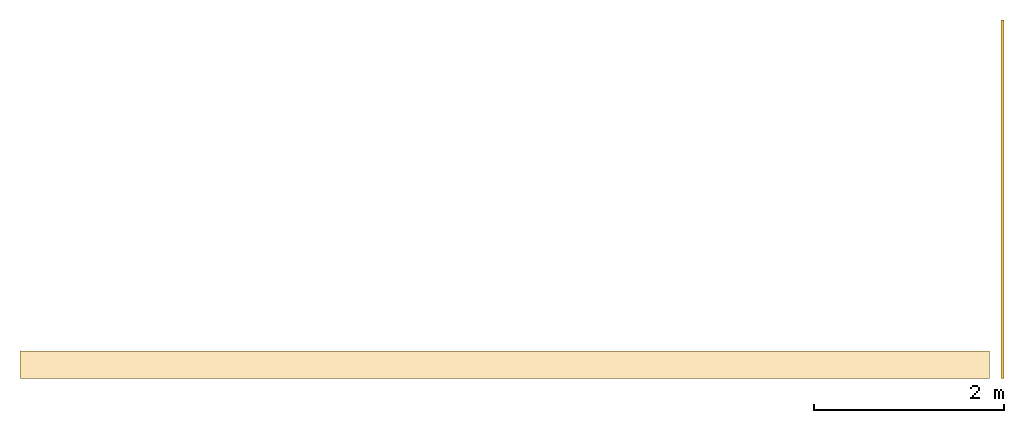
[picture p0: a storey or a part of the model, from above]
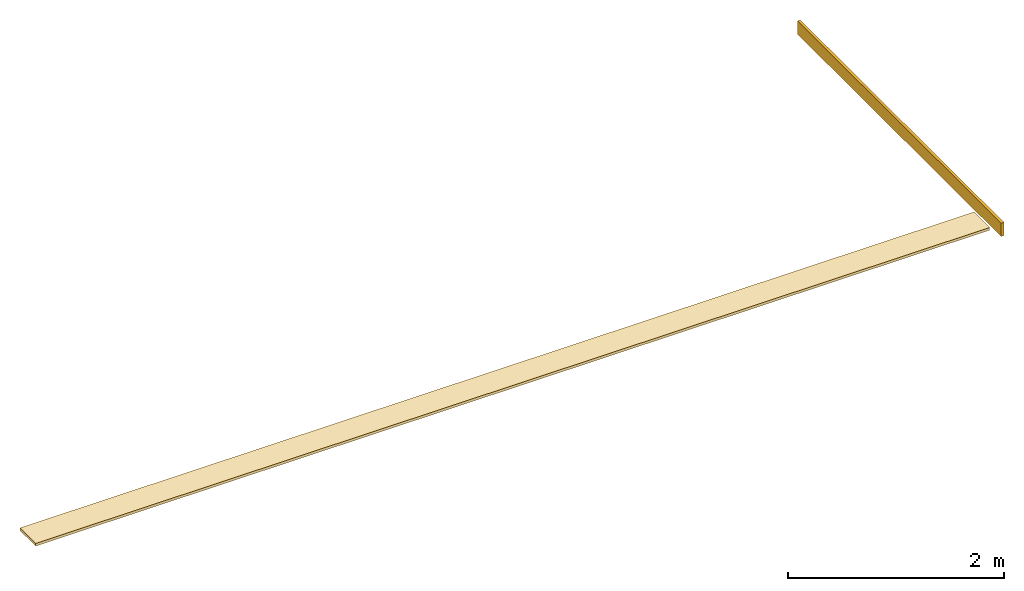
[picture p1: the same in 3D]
Properties of the parts of a building model (IFC2X3)

# File
Description: ViewDefinition [CoordinationView]
File name: GM.TO-350-208.1 (EDITED).ifc (Edited by Naviate Simple BIM 2022 version 6)
Time: 2026-03-12T20:13:48+01:00
Written by: ODA SDAI 24.12
Made in: Autodesk Revit 25.4.20.11 (ENU) - IFC 25.4.0.27

# IfcProject, A181143
LongName: UNSØ; Phase: Forprosjekt

# IfcSite (4)
Name | RefLatitude | RefLongitude | RefElevation (mm)
ENGM | 42, 24, 53, 508911 | -71, -15, -29, -58837 | -4.85124e-10
Gardermoen |  |  | 0
Default | 42, 23, 13, 199999 | -71, -14, -31, -199999 | 0 | Title Text - Mottaker 01 Firma_CW: Avinor; Mottaker 06 Kontaktperson _CW: Martin Liudalen; Mottaker 08 Kontaktperson _CW: Jesper Mæx Moe; Mottaker 02 Funksjon_CW: BL; Modellstatus_CW: Beskriv kort om status til modellen og hvilke område som er kontrollert.; Mottaker 07 Funksjon_CW: RIKT; Mottaker 05 Firma _CW: COWI/AAS-JAKOBSEN; Mottaker 06 Firma _CW: COWI/ASPLAN VIAK; Mottaker 07 Firma _CW: COWI/ASPLAN VIAK; Mottaker 05 Funksjon_CW: RIB; Mottaker 06 Funksjon_CW: RIE; Mottaker 08 Funksjon_CW: RIV; Mottaker 04 Funksjon_CW: ARK; Mottaker 02 Firma _CW: SWECO; Mottaker 10 Funksjon_CW: RIBR; Mottaker 07 Kontaktperson _CW: Kent Fagerli; Mottaker 02 Kontaktperson _CW: Øyvind Taule; Mottaker 03 Kontaktperson _CW: Kjetil Hoftvedt; Mottaker 03 Funksjon_CW: PGL; Mottaker 01 Funksjon_CW: BH; Mottaker 05 Kontaktperson _CW: Magne Fredheim; Mottaker 04 Kontaktperson _CW: Ivar Ivarsøy; Mottaker 03 Firma _CW: COWI; Mottaker 08 Firma _CW: COWI; Mottaker 01 Kontaktperson _CW: Kontakperson; Mottaker 04 Firma _CW: NORDIC; Other - Client Name: Avinor; Project Name: Utvidelse non-schengen; Category: Project Information; Project Status: Utførelse; Project Address: Gardermoen; Project Number: A173040; Project Issue Date: 24.12.2013; Identity Data - Oppdragsansvarlig_CW: Kjetil Hoftvedt; Workset: Project Info; Edited by: tagr
ENGM | 59, 54, 44, 239196 | 10, 45, 0, 0 | 0 | MagiCAD Pset_Site - Reference longitude: 10, 45, 0, 0; Reference elevation: 0; Reference latitude: 59, 54, 44, 239196; Name: ENGM

# IfcBuilding (4)
Name
TH | LongName: TH; Pset_BuildingCommon - NumberOfStoreys: 8
THO
 | Pset_BuildingCommon - NumberOfStoreys: 5; Identity Data - Oppdragsansvarlig_CW: Kjetil Hoftvedt; Workset: Project Info; Edited by: tagr; Other - Client Name: Avinor; Project Name: Utvidelse non-schengen; Category: Project Information; Project Status: Utførelse; Project Address: Gardermoen; Project Number: A173040; Project Issue Date: 24.12.2013; Title Text - Mottaker 01 Firma_CW: Avinor; Mottaker 06 Kontaktperson _CW: Martin Liudalen; Mottaker 08 Kontaktperson _CW: Jesper Mæx Moe; Mottaker 02 Funksjon_CW: BL; Modellstatus_CW: Beskriv kort om status til modellen og hvilke område som er kontrollert.; Mottaker 07 Funksjon_CW: RIKT; Mottaker 05 Firma _CW: COWI/AAS-JAKOBSEN; Mottaker 06 Firma _CW: COWI/ASPLAN VIAK; Mottaker 07 Firma _CW: COWI/ASPLAN VIAK; Mottaker 08 Funksjon_CW: RIV; Mottaker 06 Funksjon_CW: RIE; Mottaker 05 Funksjon_CW: RIB; Mottaker 04 Funksjon_CW: ARK; Mottaker 02 Firma _CW: SWECO; Mottaker 10 Funksjon_CW: RIBR; Mottaker 07 Kontaktperson _CW: Kent Fagerli; Mottaker 02 Kontaktperson _CW: Øyvind Taule; Mottaker 03 Kontaktperson _CW: Kjetil Hoftvedt; Mottaker 03 Funksjon_CW: PGL; Mottaker 01 Funksjon_CW: BH; Mottaker 05 Kontaktperson _CW: Magne Fredheim; Mottaker 04 Kontaktperson _CW: Ivar Ivarsøy; Mottaker 03 Firma _CW: COWI; Mottaker 08 Firma _CW: COWI; Mottaker 01 Kontaktperson _CW: Kontakperson; Mottaker 04 Firma _CW: NORDIC
TH | MagiCAD Pset_Building - Building name: TH

# IfcBuildingStorey (3)
Name | In | Elevation (mm)
Nivå G | THO | 0
Nivå F | THO | 0
Nivå F - 0,7 m | TH | 210200 | MagiCAD Pset_Storey - Name: Nivå F - 0,7 m

# IfcBuildingStorey: Level:CW_Level Elektro, Nivå F - 0,7 m
LongName: Nivå F - 0,7 m; Elevation: 210200 mm
Constraints(Type) - Elevation Base: Survey Point
Pset_ProductRequirements - Name: Nivå F - 0,7 m; sets with these values: 2
Identity Data - Name: Nivå F - 0,7 m; Building Story: yes; Structural: no; Workset: Shared Levels and Grids
Dimensions - Computation Height: 0 mm
Other - Type Id: 305; Family and Type: Level: CW_Level Elektro; Category: Levels; Family: Level; Type: CW_Level Elektro
Constraints - Elevation: 210200 mm
Identity Data(Type) - Workset: Level Types; Type Name: CW_Level Elektro
Graphics(Type) - Symbol: CW Nivåhode : COWI Nivåhode; Line Pattern: Grid Line; Color: 0; Symbol at End 1 Default: yes; Symbol at End 2 Default: yes; Line Weight: 1
Other(Type) - Category: Levels; Family Name: Level

# IfcBuildingStorey: Level:T2 - Kote, Nivå F - 0,7 m
In: TH
LongName: Nivå F - 0,7 m; Elevation: 210200 mm
Pset_ProductRequirements - Name: Nivå F - 0,7 m; sets with these values: 2

# IfcBuildingElementProxy: System Panel:A255 - HI-L01 - SP (10)
In: Nivå F - 0,7 m
Type - Material: lamellhimling(Panel)
Pset_BuildingElementProxyCommon - Reference: A255 - HI-L01 - SP; sets with these values: 2
AVINOR - 08_Status: S4; 05_ID-nummer: +TH=255.002-ID0011; 07_Fase: F90; 02_Prosjekt: A173040; 06_Omrade: TH; 04_Kontrakt: 185259; 03_Ansvar: 185239; 01_Lufthavnkode: ENGM
ePset_LocationTool - Splitting: ORIGINAL
ePset_Simplebim - Assembly Level: Leaf
ePset_SimplebimBasicQuantities - Height (Simplebim): 75 mm
Name (System Panel:A255 - HI-L01 - SP:...) | Area, largest surface, net (Simplebim) (m2) | Volume, net (Simplebim) (m3) | Thickness (Simplebim) (mm) | Length (Simplebim) (mm)
51589264 | 2.73781 | 0.205336 | 805 | 3600
51589265 | 3.07997 | 0.230997 | 900 | 3600
51589266 | 3.07981 | 0.230986 | 900 | 3600
51589267 | 3.07997 | 0.230997 | 900 | 3600
51589947 | 2.74905 | 0.206179 | 804.8 | 3600
51589461 | 0.435362 | 0.0326522 | 542.5 | 805
51589462 | 0.403017 | 0.0302263 | 452 | 900
51589463 | 0.40325 | 0.0302438 | 452 | 900
51589464 | 0.40325 | 0.0302438 | 452 | 900
51589948 | 0.35963 | 0.0269722 | 452 | 804.8

# IfcColumn: D20 (16)
In: Nivå F
Description: D20; Material: STEEL/S355
Pset_ColumnCommon - Reference: D20
ePset_LocationTool - Splitting: ORIGINAL
ePset_SimplebimBasicQuantities - Weight, as steel (Simplebim): 0.555079 kg; Volume, net (Simplebim): 0.0000707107 m3; Area, sides, net (Simplebim): 0.0153073 m2; Width (Simplebim): 20 mm; Depth (Simplebim): 20 mm; Height (Simplebim): 250 mm
ePset_Simplebim - Assembly Level: Leaf
Tekla Quantity - AREA_NET: 0.01587 m2; AREA_GROSS: 0.01587 m2; WEIGTH_GROSS: 0.55508 kg; WEIGTH_NET: 0.55508 kg; Width: 20 mm; Heigth: 20 mm; Length: 250 mm; VOLUME_GROSS: 0.00006 m3; VOLUME_NET: 0.00006 m3
AVINOR - 05_ID-nummer: +TH=222.027; 08_Status: S4; 07_Fase: F90; 04_Kontrakt: 185257; 02_Prosjekt: A173040; 06_Omrade: TH; 03_Ansvar: 185233; 01_Lufthavnkode: ENGM

# IfcColumn: D600 (4)
In: Nivå F
Description: D600
ePset_SimplebimBasicQuantities - Depth (Simplebim): 600 mm
ePset_LocationTool - Splitting: ORIGINAL
Tekla Quantity - Width: 600 mm; Heigth: 600 mm
Pset_ColumnCommon - Reference: D600
ePset_Simplebim - Assembly Level: Leaf
AVINOR - 05_ID-nummer: +TH=222.027; 08_Status: S4; 07_Fase: F90; 04_Kontrakt: 185257; 02_Prosjekt: A173040; 06_Omrade: TH; 03_Ansvar: 185233; 01_Lufthavnkode: ENGM
Name | Material | Volume, net (Simplebim) (m3) | Width (Simplebim) (mm) | Height (Simplebim) (mm) | Area, sides, net (Simplebim) (m2) | Weight, as steel (Simplebim) (kg) | VOLUME_GROSS (m3) = VOLUME_NET (m3) | AREA_NET (m2) = AREA_GROSS (m2) | Length (mm) | WEIGTH_GROSS (kg) = WEIGTH_NET (kg)
2 x INNSTØPNGODS | STEEL/S355 | 0.00844746 | 30 | 600 | 0.0564906 | 66.3126 | 0.00845 | 0.61965 | 30 | 66.3126
2 x PREFABSØYLE | CONCRETE/C45/55 | 1.03481 | 600 | 3675 | 6.92009 | 8123.29 | 1.03481 | 7.48326 | 3675 | 2483.55

# IfcColumn: HEA180 (2)
In: Nivå F
Description: HEA180; Material: STEEL/S355
ePset_LocationTool - Splitting: ORIGINAL
Tekla Quantity - AREA_GROSS: 3.72224 m2; WEIGTH_GROSS: 129.12 kg; VOLUME_GROSS: 0.01645 m3; Heigth: 171 mm; Width: 180 mm; Length: 3635 mm
AVINOR - 08_Status: S4; 07_Fase: F90; 05_ID-nummer: +TH=222.037; 02_Prosjekt: A173040; 06_Omrade: TH; 04_Kontrakt: 185259; 03_Ansvar: 185233; 01_Lufthavnkode: ENGM; 09_Arbeidspakke: AP02
ePset_SimplebimBasicQuantities - Width (Simplebim): 171 mm; Depth (Simplebim): 180 mm; Height (Simplebim): 3635 mm
ePset_Simplebim - Assembly Level: Leaf
Pset_ColumnCommon - Reference: HEA180
Name | WEIGTH_NET (kg) = Weight, as steel (Simplebim) (kg) | VOLUME_NET (m3) | AREA_NET (m2) | Area, sides, net (Simplebim) (m2) | Volume, net (Simplebim) (m3)
STÅLSØYLE | 120.993 | 0.01541 | 3.75515 | 3.74648 | 0.0154131
STÅLSØYLE | 118.369 | 0.01508 | 3.68478 | 3.67612 | 0.0150788

# IfcColumn: RHS80*5, STÅLSØYLE
In: Nivå F
Description: RHS80*5; Material: STEEL/S355
Pset_ColumnCommon - Reference: RHS80*5
AVINOR - 08_Status: S4; 07_Fase: F90; 05_ID-nummer: +TH=222.036; 02_Prosjekt: A173040; 06_Omrade: TH; 04_Kontrakt: 185259; 03_Ansvar: 185233; 09_Arbeidspakke: AP01; 01_Lufthavnkode: ENGM
ePset_LocationTool - Splitting: ORIGINAL
ePset_SimplebimBasicQuantities - Weight, as steel (Simplebim): 42.7433 kg; Area, sides, net (Simplebim): 2.178 m2; Volume, net (Simplebim): 0.005445 m3; Width (Simplebim): 80 mm; Depth (Simplebim): 80 mm; Height (Simplebim): 3630 mm
ePset_Simplebim - Assembly Level: Leaf
Tekla Quantity - WEIGTH_NET: 42.7433 kg; AREA_NET: 1.1632 m2; WEIGTH_GROSS: 42.4583 kg; AREA_GROSS: 1.12167 m2; VOLUME_NET: 0.00545 m3; VOLUME_GROSS: 0.00542 m3; Width: 80 mm; Heigth: 80 mm; Length: 3630 mm

# IfcColumn: UPE180, STÅLSØYLE
In: Nivå F
Description: UPE180; Material: STEEL/S355
Pset_ColumnCommon - Reference: UPE180
Tekla Quantity - VOLUME_NET: 0.00945 m3; AREA_GROSS: 2.31318 m2; WEIGTH_NET: 74.1989 kg; VOLUME_GROSS: 0.00909 m3; AREA_NET: 2.29086 m2; Width: 75 mm; Heigth: 180 mm; Length: 3620 mm; WEIGTH_GROSS: 71.3267 kg
AVINOR - 08_Status: S4; 07_Fase: F90; 05_ID-nummer: +TH=222.038; 02_Prosjekt: A173040; 06_Omrade: TH; 04_Kontrakt: 185259; 03_Ansvar: 185233; 01_Lufthavnkode: ENGM; 09_Arbeidspakke: AP02
ePset_SimplebimBasicQuantities - Weight, as steel (Simplebim): 74.1989 kg; Volume, net (Simplebim): 0.0094521 m3; Area, sides, net (Simplebim): 2.28548 m2; Width (Simplebim): 75 mm; Depth (Simplebim): 180 mm; Height (Simplebim): 3620 mm
ePset_Simplebim - Assembly Level: Leaf
ePset_LocationTool - Splitting: ORIGINAL

# IfcCovering (6)
AVINOR - 08_Status: S4; 07_Fase: F90; 04_Kontrakt: 185257; 02_Prosjekt: A173040; 06_Omrade: TH; 03_Ansvar: 185233; 01_Lufthavnkode: ENGM
Tekla Surface Treatment - Content Type: SURFACING; Aaj_forskaltyp: 0; Aaj_forskalobjtyp: 0; IFC_BUILDING: TH; Type: Steel finish
ePset_Simplebim - Assembly Level: Leaf
Name | In | Volume, net (Simplebim) (m3) | Width (Simplebim) (mm) | Height (Simplebim) (mm) | Area, largest surface, net (Simplebim) (m2) | Length (Simplebim) (mm) | 05_ID-nummer | IFC_BUILDING_STOREY | Name | Splitting
2 x SurfaceTreatment | Nivå F | 0.0164925 | 30 | 150 | 0.54975 | 3665 | +TH=222.035 | Nivå F | BRANNBESKSØYLE | ORIGINAL | Material: Undefined/MINERALULL; Tekla Surface Treatment - Weight: 0.32985 kg; Area: 0.54975 m2
2 x SurfaceTreatment | Nivå G | 0.0886525 | 290 | 30 | 2.95508 | 10190 | +TH=223.202 | Nivå G | BRANNBESKBJELKE | RESULT
2 x SurfaceTreatment | Nivå G | 0.0169557 | 30 | 150 | 0.56519 | 3768 | +TH=223.202 | Nivå G | BRANNBESKBJELKE | RESULT

# IfcCovering: A255 - HI-L01 - Panel:A255 - HI-L01 - Panel (38)
In: Nivå F - 0,7 m
Type - PredefinedType: CEILING; Material: lamellhimling(Panel)
ePset_SimplebimBasicQuantities - Height (Simplebim): 75 mm
ePset_LocationTool - Splitting: ORIGINAL
Pset_CoveringCommon - Reference: A255 - HI-L01 - Panel; sets with these values: 2
AVINOR - 08_Status: S4; 05_ID-nummer: +TH=255.002-ID0011; 07_Fase: F90; 02_Prosjekt: A173040; 06_Omrade: TH; 04_Kontrakt: 185259; 03_Ansvar: 185239; 01_Lufthavnkode: ENGM
ePset_Simplebim - Assembly Level: Leaf
Name (A255 - HI-L01 - Panel:A255 - HI-L01 - Panel:...) | Volume, net (Simplebim) (m3) | Area, largest surface, net (Simplebim) (m2) | Length (Simplebim) (mm) | Width (Simplebim) (mm)
51590143 | 0.108071 | 1.44095 | 1790 | 805
51589183 | 0.120825 | 1.611 | 1790 | 900
51589185 | 0.120825 | 1.611 | 1790 | 900
51589187 | 0.120825 | 1.611 | 1790 | 900
51589189 | 0.120825 | 1.611 | 1790 | 900
51589191 | 0.120825 | 1.611 | 1790 | 900
51589193 | 0.120825 | 1.611 | 1790 | 900
51589195 | 0.120825 | 1.611 | 1790 | 900
51589197 | 0.120825 | 1.611 | 1790 | 900
51589199 | 0.120825 | 1.611 | 1790 | 900
51589201 | 0.120825 | 1.611 | 1790 | 900
51589203 | 0.120825 | 1.611 | 1790 | 900
51589205 | 0.120825 | 1.611 | 1790 | 900
51589207 | 0.120825 | 1.611 | 1790 | 900
51589209 | 0.120825 | 1.611 | 1790 | 900
51589211 | 0.0986469 | 1.31529 | 1790 | 734.8
51590144 | 0.243 | 3.24 | 3600 | 900
51589216 | 0.243 | 3.24 | 3600 | 900
51589217 | 0.243 | 3.24 | 3600 | 900
51589218 | 0.243 | 3.24 | 3600 | 900
51589219 | 0.243 | 3.24 | 3600 | 900
51589220 | 0.243 | 3.24 | 3600 | 900
51589221 | 0.243 | 3.24 | 3600 | 900
51589222 | 0.243 | 3.24 | 3600 | 900
51590145 | 0.243 | 3.24 | 3600 | 900
51589226 | 0.243 | 3.24 | 3600 | 900
51589227 | 0.243 | 3.24 | 3600 | 900
51589232 | 0.03051 | 0.4068 | 900 | 452
51589233 | 0.03051 | 0.4068 | 900 | 452
51589234 | 0.03051 | 0.4068 | 900 | 452
51589235 | 0.03051 | 0.4068 | 900 | 452
51589236 | 0.03051 | 0.4068 | 900 | 452
51589237 | 0.03051 | 0.4068 | 900 | 452
51589238 | 0.03051 | 0.4068 | 900 | 452
51589239 | 0.03051 | 0.4068 | 900 | 452
51589242 | 0.03051 | 0.4068 | 900 | 452
51589243 | 0.03051 | 0.4068 | 900 | 452
51589244 | 0.03051 | 0.4068 | 900 | 452

# IfcCovering: Sloped Glazing:A255 - HI-L01- Lamellhimling, Sloped Glazing:A255 - HI-L01- Lamellhimling:51588579
In: Nivå F - 0,7 m
PredefinedType: CEILING
ePset_SimplebimBasicQuantities - Volume, net (Simplebim): 6.16171 m3; Length: 14209.8 mm; Height: 75 mm; Width: 5932.5 mm
ePset_Simplebim - Assembly Level: Topmost
Pset_CoveringCommon - Reference: A255 - HI-L01- Lamellhimling; TotalThickness: 100 mm
AVINOR - 08_Status: S4; 05_ID-nummer: +TH=255.002-ID0011; 07_Fase: F90; 02_Prosjekt: A173040; 06_Omrade: TH; 04_Kontrakt: 185259; 03_Ansvar: 185239; 01_Lufthavnkode: ENGM
Pset_QuantityTakeOff - Reference: A255 - HI-L01- Lamellhimling

# IfcCurtainWall: Curtain Wall:A240 - IV-M01 Metallforheng (2)
In: Nivå F - 0,7 m
ePset_Simplebim - Assembly Level: Topmost
Pset_QuantityTakeOff - Reference: A240 - IV-M01 Metallforheng
ePset_SimplebimBasicQuantities - Width: 120 mm; Height: 3300 mm
AVINOR - 08_Status: S4; 07_Fase: F90; 02_Prosjekt: A173040; 06_Omrade: TH; 03_Ansvar: 185239; 04_Kontrakt: 185259; 01_Lufthavnkode: ENGM
Pset_CurtainWallCommon - Reference: A240 - IV-M01 Metallforheng; IsExternal: no
Name (Curtain Wall:A240 - IV-M01 Metallforheng:...) | Volume, net (Simplebim) (m3) | Length (mm) | 05_ID-nummer
39125915 | 0.164689 | 8970 | +TH=243.001-IR0037
39125955 | 0.0800496 | 4360 | +TH=243.001-IR0038

# IfcCurtainWall: Curtain Wall:A242 - IV-G10_glassvegg, innspent bunn/topp (2)
In: Nivå F - 0,7 m
Pset_QuantityTakeOff - Reference: A242 - IV-G10_glassvegg, innspent bunn/topp
ePset_Simplebim - Assembly Level: Topmost
Pset_CurtainWallCommon - IsExternal: no; Reference: A242 - IV-G10_glassvegg, innspent bunn/topp
ePset_SimplebimBasicQuantities - Width: 50 mm; Height: 3150 mm
AVINOR - 08_Status: S4; 07_Fase: F90; 05_ID-nummer: +TH=242.210; 02_Prosjekt: A173040; 06_Omrade: TH; 03_Ansvar: 185239; 04_Kontrakt: 185259; 01_Lufthavnkode: ENGM
Name (Curtain Wall:A242 - IV-G10_glassvegg, innspent bunn/topp:...) | Volume, net (Simplebim) (m3) | Length (mm)
41783049 | 0.138885 | 1945
45410759 | 0.138168 | 1919

# IfcCurtainWall: Curtain Wall:A245 - SF-04, Curtain Wall:A245 - SF-04:56780964
In: Nivå F - 0,7 m
ePset_Simplebim - Assembly Level: Topmost
AVINOR - 08_Status: S4; 07_Fase: F90; 05_ID-nummer: +TH=243.001-IM0030; 02_Prosjekt: A173040; 06_Omrade: TH; 03_Ansvar: 185239; 04_Kontrakt: 185259; 01_Lufthavnkode: ENGM
Pset_QuantityTakeOff - Reference: A245 - SF-04
Pset_CurtainWallCommon - IsExternal: no; Reference: A245 - SF-04
ePset_SimplebimBasicQuantities - Volume, net (Simplebim): 0.00564095 m3; Width: 142 mm; Length: 214.5 mm; Height: 3100 mm

# IfcDistributionPort, Port_5494839_1
Description: Flow; FlowDirection: SOURCEANDSINK
ePset_Simplebim - Assembly Level: Leaf

# IfcDoor: A20 - Slagdør - Enkel:A243 - DI_LTO - 0990x2240 mm, A20 - Slagdør - Enkel:A243 - DI_LTO - 0990x2240 mm:28980963
In: Nivå F - 0,7 m
Type - OperationType: SINGLE_SWING_RIGHT; ParameterTakesPrecedence: no; Sizeable: no; Material: _NSW Stål - rustfritt, N_Door - Handle, Type_B_Wood_Oak-washed-white_2810x1190
Type - IfcDoorPanelProperties - PanelOperation: SWINGING
OverallHeight: 2260 mm; OverallWidth: 1010 mm
AVINOR - 08_Status: S4; 07_Fase: F90; 05_ID-nummer: +TH=243.001-IO2806; 02_Prosjekt: A173040; 06_Omrade: TH; 03_Ansvar: 185239; 04_Kontrakt: 185259; 01_Lufthavnkode: ENGM
ePset_LocationTool - Splitting: ORIGINAL
Pset_QuantityTakeOff - Reference: A243 - DI_LTO - 0990x2240 mm
ePset_SimplebimBasicQuantities - Area, opening (Simplebim): 2.2826 m2; Height, opening (Simplebim): 2260 mm; Width, opening (Simplebim): 1010 mm; Width (Simplebim): 990 mm; Height (Simplebim): 2240 mm; Length, frame (Simplebim): 5470 mm; Area (Simplebim): 2.2176 m2
ePset_Simplebim - Assembly Level: Leaf
Pset_DoorCommon - IsExternal: no; Reference: A243 - DI_LTO - 0990x2240 mm
Identity Data - CQFireRequirement: EI60Sa; CQAcousticRequirement: 33dB

# IfcDoor: A20 - Slagdør - Enkel:A243 - DI_SSO - 1090x2240 mm, A20 - Slagdør - Enkel:A243 - DI_SSO - 1090x2240 mm:45410761
In: Nivå F - 0,7 m
Type - OperationType: SINGLE_SWING_RIGHT; ParameterTakesPrecedence: no; Sizeable: no; Material: _NSW Stål - rustfritt, N_Door - Handle, _NSW Stål, Type_B_Wood_Oak-washed-white_2810x1190
Type - IfcDoorPanelProperties - PanelOperation: SWINGING
OverallHeight: 2260 mm; OverallWidth: 1110 mm
Pset_DoorCommon - Reference: A243 - DI_SSO - 1090x2240 mm; IsExternal: no; SecurityRating: DK01
Pset_QuantityTakeOff - Reference: A243 - DI_SSO - 1090x2240 mm
ePset_SimplebimBasicQuantities - Area, opening (Simplebim): 2.5086 m2; Height, opening (Simplebim): 2260 mm; Area (Simplebim): 2.4416 m2; Width (Simplebim): 1090 mm; Width, opening (Simplebim): 1110 mm; Height (Simplebim): 2240 mm; Length, frame (Simplebim): 5570 mm
AVINOR - 08_Status: S4; 07_Fase: F90; 05_ID-nummer: +TH=243.001-IP0436; 02_Prosjekt: A173040; 06_Omrade: TH; 03_Ansvar: 185239; 04_Kontrakt: 185259; 01_Lufthavnkode: ENGM
ePset_LocationTool - Splitting: ORIGINAL
ePset_Simplebim - Assembly Level: Leaf

# IfcFlowSegment: Sirkulær kanal, Sirkulær kanal, forsinket stål
In: Nivå F - 0,7 m
Type - Description: Sirkulær kanal, forsinket stål; PredefinedType: RIGIDSEGMENT
MagiCAD Pset_Duct - Description: Sirkulær kanal, forsinket stål; qv_SizingFlow_ls: 0 m3/s; dpTot_SizingFlow_Pa: 0 kPa; pTot_SizingFlow_Pa: 0 kPa; v_SizingFlow_ms: 0 m/s; Insulation_thickness_mm: 0 mm; Length_mm: 285.961 mm; Product variable 4: 2; UserCode: KK002T
ePset_LocationTool - Splitting: ORIGINAL
ePset_SimplebimBasicQuantities - Height (Simplebim): 160 mm; Width (Simplebim): 160 mm; Length (Simplebim): 286 mm
ePset_Simplebim - Assembly Level: Leaf
Group: +TH=360.091 TL

# IfcFlowTerminal: Datauttak dobbel Vegg:Datauttak dobbel Vegg - IKT, Datauttak dobbel Vegg:Datauttak dobbel Vegg - IKT:5494839
In: Nivå F - 0,7 m
Type - PredefinedType: COMMUNICATIONSOUTLET; Material: <Unnamed>
Type - Other - Category: Data Devices; Family Name: Datauttak dobbel Vegg
Type - Constraints - Default Elevation: 0 mm
Type - Dimensions - L2D: 71 mm; W2D: 22 mm
Type - Electrical Engineering - magiActivePower: 0 W; magiCosPhi: 1; magiNumberOfPoles: 1; magiVoltage: 0 V
Type - Graphics - IKT: yes; magiFamilyGeom: MagiCAD_Data socket-2; TVO: no; TVO-VDL: no; UR: no; WLAN: no
Type - Identity Data - Description: Datauttak dobbel Vegg - IKT; magi_RI_amount: 2; magiPartTypeId: 603; magiUserCode: -WD; Type Name: Datauttak dobbel Vegg - IKT; Workset: Family : Data Devices : Datauttak dobbel Vegg
Other - Family: Datauttak dobbel Vegg; Family and Type: Datauttak dobbel Vegg: Datauttak dobbel Vegg - IKT; Type: Datauttak dobbel Vegg - IKT; Type Id: 4185853
Constraints - Level: Nivå F - 0,7 m; MC_bottom_elevation: 164.406 mm; MC_top_elevation_abs: 210436 mm; MC_installation_elevation: 200 mm; Elevation from Level: 200 mm; Offset from Host: 200 mm; MC_connection_elevation: 200 mm; MC_top_elevation: 235.602 mm; MC_connection_elevation_abs: 210400 mm; MC_installation_elevation_abs: 210400 mm; Host: Level : Nivå F - 0,7 m; MC_bottom_elevation_abs: 210364 mm
AVINOR - 08_Status: S4; 07_Fase: F90; 02_Prosjekt: A173040; 06_Omrade: TH; 03_Ansvar: 185233; 04_Kontrakt: 185260; 05_ID-nummer: +TH=574.014-WD0197; 01_Lufthavnkode: ENGM
Pset_DistributionFlowElementCommon - Reference: Datauttak dobbel Vegg - IKT; sets with these values: 2
Phasing - Phase Created: Fase 1
ePset_LocationTool - Splitting: ORIGINAL
Graphics - Boks innfelt: yes
Identity Data - 08_Status: S4; 07_Fase: F90; ID-nummer2: +TH=574.014-WD0198; magiSystemCode: 574; Workset: 574-Spredenett; 02_Prosjekt: A173040; 06_Omrade: TH; Comments: PYLON KABEL.F VIA NIVÅ D; magi_RI_1: 0197; 03_Ansvar: 185233; magi_RI_group: +TH=574.014; magi_RI_format: +TH=574.014; Mark: 338; 04_Kontrakt: 185260; 05_ID-nummer: +TH=574.014-WD0197; 01_Lufthavnkode: ENGM; magi_RI_2: 0198
ePset_Simplebim - Assembly Level: Leaf
Dimensions - ang2D: 0 deg; dX2D: 0 mm; dY2D: 0 mm; Volume: 0.00000696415 m3; Area: 0.00278709 m2

# IfcFlowTerminal: TLH-160, TILLUFTSVENTIL
In: Nivå F - 0,7 m
Type - Description: TILLUFTSVENTIL
ePset_LocationTool - Splitting: ORIGINAL
MagiCAD Pset_AirTerminal - Description: TILLUFTSVENTIL; Manufacturer: TROX Auranor; ProductCode: TLH-160; dpTot_SizingFlow_Pa: 0 kPa; qv_SizingFlow_ms: 0 m/s; qv_SizingFlow_ls: 41.667 m3/s; ConnectionSize_mm: 160; User Code: AS
ePset_Simplebim - Assembly Level: Leaf
Group: +TH=360.091 TL

# IfcMember: Rectangular Mullion:A240 - Metallforheng, bunnkasse BxH 120x150mm (2)
In: Nivå F - 0,7 m
Type - PredefinedType: MULLION; Material: Metal - Stainless Steel(Dark)
ePset_Simplebim - Assembly Level: Leaf
Pset_MemberCommon - Reference: A240 - Metallforheng, bunnkasse BxH 120x150mm; IsExternal: no
Pset_QuantityTakeOff - Reference: A240 - Metallforheng, bunnkasse BxH 120x150mm
ePset_SimplebimBasicQuantities - Width (Simplebim): 120 mm; Height (Simplebim): 150 mm
ePset_LocationTool - Splitting: ORIGINAL
AVINOR - 08_Status: S4; 07_Fase: F90; 02_Prosjekt: A173040; 06_Omrade: TH; 03_Ansvar: 185239; 04_Kontrakt: 185259; 01_Lufthavnkode: ENGM
Name (Rectangular Mullion:A240 - Metallforheng, bunnkasse BxH 120x150mm:...) | Span (mm) = Length (Simplebim) (mm) | Weight, as steel (Simplebim) (kg) | Volume, net (Simplebim) (m3) | Area, sides, net (Simplebim) (m2) | 05_ID-nummer
39125917 | 8970 | 227.58 | 0.028991 | 7.39774 | +TH=243.001-IR0037
39125957 | 4360 | 110.618 | 0.0140915 | 3.5991 | +TH=243.001-IR0038

# IfcMember: Rectangular Mullion:A240 - Metallforheng, bunnkasse topp BxH 120x150mm (2)
In: Nivå F - 0,7 m
Type - PredefinedType: MULLION; Material: Metal - Stainless Steel(Dark)
ePset_Simplebim - Assembly Level: Leaf
Pset_QuantityTakeOff - Reference: A240 - Metallforheng, bunnkasse topp BxH 120x150mm
ePset_LocationTool - Splitting: ORIGINAL
AVINOR - 08_Status: S4; 07_Fase: F90; 02_Prosjekt: A173040; 06_Omrade: TH; 03_Ansvar: 185239; 04_Kontrakt: 185259; 01_Lufthavnkode: ENGM
ePset_SimplebimBasicQuantities - Width (Simplebim): 120 mm; Height (Simplebim): 300 mm
Pset_MemberCommon - Reference: A240 - Metallforheng, bunnkasse topp BxH 120x150mm; IsExternal: no
Name (Rectangular Mullion:A240 - Metallforheng, bunnkasse topp BxH 120x150mm:...) | 05_ID-nummer | Volume, net (Simplebim) (m3) | Area, sides, net (Simplebim) (m2) | Weight, as steel (Simplebim) (kg) | Length (Simplebim) (mm) = Span (mm)
41727951 | +TH=243.001-IR0037 | 0.0551834 | 12.6421 | 433.19 | 8970
41727954 | +TH=243.001-IR0038 | 0.0268227 | 6.15118 | 210.558 | 4360

# IfcMember: Rectangular Mullion:A240 - innspenningsprofil glassvegg (8)
In: Nivå F - 0,7 m
Type - PredefinedType: MULLION; Material: Aluminium
Pset_MemberCommon - Reference: A240 - innspenningsprofil glassvegg; IsExternal: no
ePset_Simplebim - Assembly Level: Leaf
ePset_LocationTool - Splitting: ORIGINAL
Pset_QuantityTakeOff - Reference: A240 - innspenningsprofil glassvegg
ePset_SimplebimBasicQuantities - Width (Simplebim): 50 mm; Height (Simplebim): 150 mm
AVINOR - 08_Status: S4; 07_Fase: F90; 05_ID-nummer: +TH=242.210; 02_Prosjekt: A173040; 06_Omrade: TH; 03_Ansvar: 185239; 04_Kontrakt: 185259; 01_Lufthavnkode: ENGM
Name (Rectangular Mullion:A240 - innspenningsprofil glassvegg:...) | Span (mm) = Length (Simplebim) (mm) | Volume, net (Simplebim) (m3) | Area, sides, net (Simplebim) (m2) | Weight, as steel (Simplebim) (kg)
41783053 | 965 | 0.0072375 | 0.401 | 56.8144
41783054 | 965 | 0.0072375 | 0.401 | 56.8144
45264527 | 980 | 0.0071625 | 0.400107 | 56.2256
45264530 | 965 | 0.0072375 | 0.401 | 56.8144
41728014 | 959.5 | 0.00719625 | 0.3988 | 56.4906
41783202 | 959.5 | 0.00719625 | 0.3988 | 56.4906
41783204 | 959.5 | 0.00719625 | 0.3988 | 56.4906
45410758 | 959.5 | 0.00719625 | 0.3988 | 56.4906

# IfcMember: Rectangular Mullion:A242 - Sprosse - 20(post)+164.5(dekkprofil) x 50 mm_hvit, Rectangular Mullion:A242 - Sprosse - 20(post)+164.5(dekkprofil) x 50 mm_hvit:56780966
In: Nivå F - 0,7 m
Type - PredefinedType: MULLION; Material: Aluminium
ePset_Simplebim - Assembly Level: Leaf
ePset_LocationTool - Splitting: ORIGINAL
AVINOR - 08_Status: S4; 07_Fase: F90; 05_ID-nummer: +TH=243.001-IM0030; 02_Prosjekt: A173040; 06_Omrade: TH; 03_Ansvar: 185239; 04_Kontrakt: 185259; 01_Lufthavnkode: ENGM
Pset_QuantityTakeOff - Reference: A242 - Sprosse - 20(post)+164.5(dekkprofil) x 50 mm_hvit
ePset_SimplebimBasicQuantities - Area, sides, net (Simplebim): 0.085048 m2; Width (Simplebim): 142 mm; Length (Simplebim): 184.5 mm; Volume, net (Simplebim): 0.00130995 m3; Weight, as steel (Simplebim): 10.2831 kg; Height (Simplebim): 50 mm
Pset_MemberCommon - IsExternal: no; Reference: A242 - Sprosse - 20(post)+164.5(dekkprofil) x 50 mm_hvit; Span: 142 mm

# IfcPlate: A243 - Beskyttelse lyssensor metallforheng:A243 - Beskyttelse lyssensor metallforheng (3)
In: Nivå F - 0,7 m
Type - Material: <Unnamed>
ePset_Simplebim - Assembly Level: Leaf
ePset_LocationTool - Splitting: ORIGINAL
Pset_PlateCommon - Reference: A243 - Beskyttelse lyssensor metallforheng; IsExternal: no
Pset_QuantityTakeOff - Reference: A243 - Beskyttelse lyssensor metallforheng
AVINOR - 08_Status: S4; 07_Fase: F90; 05_ID-nummer: +TH=245.180; 02_Prosjekt: A173040; 06_Omrade: TH; 03_Ansvar: 185239; 04_Kontrakt: 185259; 01_Lufthavnkode: ENGM
Name (A243 - Beskyttelse lyssensor metallforheng:A243 - Beskyttelse lyssensor metallforheng:...) | Weight, as steel (Simplebim) (kg) | Volume, net (Simplebim) (m3) | Area, largest surface, net (Simplebim) (m2)
58140314 | 11.775 | 0.0015 | 0.375
58140433 | 26.376 | 0.00336 | 0.84
58140562 | 18.369 | 0.00234 | 0.585

# IfcPlate: A245 - SF:A245 - SF-04, A245 - SF:A245 - SF-04:56780965
In: Nivå F - 0,7 m
Type - PredefinedType: CURTAIN_PANEL; Material: Aluminium
ePset_Simplebim - Assembly Level: Leaf
Pset_QuantityTakeOff - Reference: A245 - SF-04
AVINOR - 08_Status: S4; 07_Fase: F90; 05_ID-nummer: +TH=243.001-IM0030; 02_Prosjekt: A173040; 06_Omrade: TH; 03_Ansvar: 185239; 04_Kontrakt: 185259; 01_Lufthavnkode: ENGM
Pset_PlateCommon - IsExternal: no; Reference: A245 - SF-04
ePset_LocationTool - Splitting: ORIGINAL
ePset_SimplebimBasicQuantities - Weight, as steel (Simplebim): 33.9983 kg; Volume, net (Simplebim): 0.004331 m3; Area, largest surface, net (Simplebim): 0.4331 m2

# IfcPlate: PL10*100, STÅLSØYLE
In: Nivå F
Description: PL10*100; Material: STEEL/S355
ePset_Simplebim - Assembly Level: Leaf
Pset_PlateCommon - Reference: PL10*100
AVINOR - 08_Status: S4; 07_Fase: F90; 05_ID-nummer: +TH=222.036; 02_Prosjekt: A173040; 06_Omrade: TH; 04_Kontrakt: 185259; 03_Ansvar: 185233; 09_Arbeidspakke: AP01; 01_Lufthavnkode: ENGM
ePset_SimplebimBasicQuantities - Volume, net (Simplebim): 0.000219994 m3; Area, largest surface, net (Simplebim): 0.0219994 m2; Weight, as steel (Simplebim): 1.72695 kg
Tekla Quantity - VOLUME_GROSS: 0.00022 m3; VOLUME_NET: 0.00022 m3; Heigth: 99.9992 mm; Length: 219.995 mm; AREA_GROSS: 0.022 m2; Width: 10 mm; AREA_NET: 0.0504 m2; WEIGTH_GROSS: 1.72695 kg; WEIGTH_NET: 1.72695 kg
ePset_LocationTool - Splitting: ORIGINAL

# IfcPlate: PL15*300 (3)
In: Nivå F
Description: PL15*300; Material: STEEL/S355
ePset_LocationTool - Splitting: ORIGINAL
ePset_Simplebim - Assembly Level: Leaf
Pset_PlateCommon - Reference: PL15*300
ePset_SimplebimBasicQuantities - Weight, as steel (Simplebim): 10.5973 kg; Volume, net (Simplebim): 0.00134998 m3; Area, largest surface, net (Simplebim): 0.0899984 m2
AVINOR - 08_Status: S4; 07_Fase: F90; 02_Prosjekt: A173040; 06_Omrade: TH; 04_Kontrakt: 185259; 03_Ansvar: 185233; 01_Lufthavnkode: ENGM; 09_Arbeidspakke: AP02
Tekla Quantity - Heigth: 299.999 mm; WEIGTH_GROSS: 10.5973 kg; WEIGTH_NET: 10.5973 kg; Width: 15 mm; VOLUME_GROSS: 0.00135 m3; VOLUME_NET: 0.00135 m3; AREA_GROSS: 0.09 m2; AREA_NET: 0.198 m2; Length: 299.995 mm
Name | 05_ID-nummer
STÅLSØYLE | +TH=222.038
2 x STÅLSØYLE | +TH=222.037

# IfcPlate: System Panel:A240 - IV-M01 Metallforheng (2)
In: Nivå F - 0,7 m
Type - PredefinedType: CURTAIN_PANEL; Material: Metallforheng
ePset_Simplebim - Assembly Level: Leaf
Pset_QuantityTakeOff - Reference: A240 - IV-M01 Metallforheng
ePset_LocationTool - Splitting: ORIGINAL
AVINOR - 08_Status: S4; 07_Fase: F90; 02_Prosjekt: A173040; 06_Omrade: TH; 03_Ansvar: 185239; 04_Kontrakt: 185259; 01_Lufthavnkode: ENGM
Pset_PlateCommon - Reference: A240 - IV-M01 Metallforheng; IsExternal: no
Name (System Panel:A240 - IV-M01 Metallforheng:...) | Area, largest surface, net (Simplebim) (m2) | Volume, net (Simplebim) (m3) | Weight, as steel (Simplebim) (kg) | 05_ID-nummer
39125916 | 26.8382 | 0.0805147 | 632.041 | +TH=243.001-IR0037
39125956 | 13.0451 | 0.0391354 | 307.213 | +TH=243.001-IR0038

# IfcPlate: System Panel:A245 - PA-G06 (4)
In: Nivå F - 0,7 m
Type - PredefinedType: CURTAIN_PANEL; Material: Glass
ePset_Simplebim - Assembly Level: Leaf
AVINOR - 08_Status: S4; 07_Fase: F90; 05_ID-nummer: +TH=242.210-IG0001; 02_Prosjekt: A173040; 06_Omrade: TH; 03_Ansvar: 185239; 04_Kontrakt: 185259; 01_Lufthavnkode: ENGM
Pset_PlateCommon - Reference: A245 - PA-G06; IsExternal: no
Pset_QuantityTakeOff - Reference: A245 - PA-G06
ePset_LocationTool - Splitting: ORIGINAL
Name (System Panel:A245 - PA-G06:...) | Weight, as steel (Simplebim) (kg) | Volume, net (Simplebim) (m3) | Area, largest surface, net (Simplebim) (m2)
41783052 | 431.789 | 0.055005 | 2.75025
45264525 | 431.789 | 0.055005 | 2.75025
45410757 | 429.328 | 0.0546915 | 2.73457
41783199 | 429.328 | 0.0546915 | 2.73457

# IfcSlab: 100*27000, PÅSTØP
In: Nivå F
Description: 100*27000; PredefinedType: FLOOR
Pset_SlabCommon - Reference: 100*27000
ePset_Simplebim - Assembly Level: Leaf
AVINOR - 08_Status: S4; 07_Fase: F90; 04_Kontrakt: 185257; 05_ID-nummer: +TH=251.027; 02_Prosjekt: A173040; 06_Omrade: TH; 03_Ansvar: 185233; 09_Arbeidspakke: AP01; 01_Lufthavnkode: ENGM
ePset_LocationTool - Splitting: RESULT
ePset_SimplebimBasicQuantities - Perimeter (Simplebim): 45299.7 mm; Area, sides, net (Simplebim): 4.52997 m2; Thickness (Simplebim): 100 mm; Area, largest surface, net (Simplebim): 87.6083 m2; Area, top, net (Simplebim): 87.6083 m2; Volume, net (Simplebim): 8.76083 m3

# IfcSlab: Floor:A254 - GU-K01 - Keramisk flis publikumsarealer, Floor:A254 - GU-K01 - Keramisk flis publikumsarealer:36789767
In: Nivå F - 0,7 m
Type - PredefinedType: FLOOR; Material: GU-K01_Gulvfliser i Publikumsareal 9 mm, Concrete, Sand/Cement Screed 6 mm, T2_Mørtel 55 mm
Type - Pset_SlabCommon - ThermalTransmittance: 75.5507 W/K/m2
Pset_SlabCommon - Reference: A254 - GU-K01 - Keramisk flis publikumsarealer; IsExternal: no; LoadBearing: no
ePset_Simplebim - Assembly Level: Leaf
Pset_QuantityTakeOff - Reference: A254 - GU-K01 - Keramisk flis publikumsarealer; sets with these values: 2
AVINOR - 08_Status: S4; 07_Fase: F90; 05_ID-nummer: +TH=254.104; 02_Prosjekt: A173040; 06_Omrade: TH; 04_Kontrakt: 185259; 03_Ansvar: 185239; 01_Lufthavnkode: ENGM
ePset_SimplebimBasicQuantities - Volume, net (Simplebim): 0.198426 m3; Area, top, net (Simplebim): 2.83466 m2; Area, largest surface, net (Simplebim): 2.83466 m2; Perimeter (Simplebim): 45133.7 mm; Thickness (Simplebim): 70 mm; Area, sides, net (Simplebim): 3.15936 m2
ePset_LocationTool - Splitting: RESULT

# IfcSlab: Floor:A254 - GU-M01 - Poretetting av betong inkl. avretting_61mm, Floor:A254 - GU-M01 - Poretetting av betong inkl. avretting_61mm:54035061
In: Nivå F - 0,7 m
Type - PredefinedType: FLOOR; Material: Concrete, Sand/Cement Screed 61 mm
Type - Pset_SlabCommon - ThermalTransmittance: 17.1475 W/K/m2
ePset_Simplebim - Assembly Level: Leaf
AVINOR - 08_Status: S4; 07_Fase: F90; 05_ID-nummer: +TH=254.107; 02_Prosjekt: A173040; 06_Omrade: TH; 04_Kontrakt: 185259; 03_Ansvar: 185239; 01_Lufthavnkode: ENGM
Pset_SlabCommon - IsExternal: no; LoadBearing: no; PitchAngle: 0 deg; Reference: A254 - GU-M01 - Poretetting av betong inkl. avretting_61mm
ePset_SimplebimBasicQuantities - Volume, net (Simplebim): 0.0163968 m3; Area, sides, net (Simplebim): 0.25132 m2; Area, top, net (Simplebim): 0.2688 m2; Area, largest surface, net (Simplebim): 0.2688 m2; Thickness (Simplebim): 61 mm; Perimeter (Simplebim): 4120 mm
Pset_ReinforcementBarPitchOfSlab - Reference: A254 - GU-M01 - Poretetting av betong inkl. avretting_61mm; sets with these values: 2
ePset_LocationTool - Splitting: ORIGINAL

# IfcSlab: Floor:A254 - GU-M02 - Industrimaling 70MM, Floor:A254 - GU-M02 - Industrimaling 70MM:51738642
In: Nivå F - 0,7 m
Type - PredefinedType: FLOOR; Material: 192_192_192 2 mm, _NSW - Avretting 68 mm
ePset_Simplebim - Assembly Level: Leaf
AVINOR - 08_Status: S4; 07_Fase: F90; 05_ID-nummer: +TH=254.108; 02_Prosjekt: A173040; 06_Omrade: TH; 04_Kontrakt: 185259; 03_Ansvar: 185239; 01_Lufthavnkode: ENGM
Pset_QuantityTakeOff - Reference: A254 - GU-M02 - Industrimaling 70MM; sets with these values: 2
ePset_LocationTool - Splitting: ORIGINAL
Pset_SlabCommon - IsExternal: no; LoadBearing: no; PitchAngle: 0 deg; Reference: A254 - GU-M02 - Industrimaling 70MM
ePset_SimplebimBasicQuantities - Area, largest surface, net (Simplebim): 0.16665 m2; Area, top, net (Simplebim): 0.16665 m2; Volume, net (Simplebim): 0.0116655 m3; Area, sides, net (Simplebim): 0.1645 m2; Thickness (Simplebim): 70 mm; Perimeter (Simplebim): 2350 mm

# IfcSlab: Floor:A254 - GU-M03 - Støvbinding uten averetting, Floor:A254 - GU-M03 - Støvbinding uten averetting:41918995
In: Nivå F - 0,7 m
Type - PredefinedType: FLOOR; Material: Støvbinding 1 mm
ePset_Simplebim - Assembly Level: Leaf
AVINOR - 08_Status: S4; 07_Fase: F90; 05_ID-nummer: +TH=254.109; 02_Prosjekt: A173040; 06_Omrade: TH; 04_Kontrakt: 185259; 03_Ansvar: 185239; 01_Lufthavnkode: ENGM
ePset_SimplebimBasicQuantities - Area, sides, net (Simplebim): 0.0409967 m2; Perimeter (Simplebim): 40996.7 mm; Area, largest surface, net (Simplebim): 84.4759 m2; Area, top, net (Simplebim): 84.4759 m2; Volume, net (Simplebim): 0.0844762 m3; Thickness (Simplebim): 1 mm
Pset_QuantityTakeOff - Reference: A254 - GU-M03 - Støvbinding uten averetting; sets with these values: 2
Pset_SlabCommon - Reference: A254 - GU-M03 - Støvbinding uten averetting; IsExternal: no; LoadBearing: no; PitchAngle: 0 deg
ePset_LocationTool - Splitting: ORIGINAL

# IfcSystem, +TH=360.091 TL
Description: +TH=360.091 TL

# IfcWall: A270 - KL-S04:A270 - Åpning stål ramme for dører L-profil, A270 - KL-S04:A270 - Åpning stål ramme for dører L-profil:45411551
In: Nivå F - 0,7 m
Type - Material: Metal - Stainless Steel
ePset_SimplebimBasicQuantities - Volume, net (Simplebim): 0.003257 m3; Area, side, gross, AABB (Simplebim): 2.737 m2; Area, side, net, average (Simplebim): 0.2284 m2; Area, side, net, smaller (Simplebim): 0.2284 m2; Area, side, net, larger (Simplebim): 0.2284 m2; Area, side, gross, average (Simplebim): 0.2284 m2; Area, side, gross, smaller (Simplebim): 0.2284 m2; Area, side, gross, larger (Simplebim): 0.2284 m2; Area, largest surface, net (Simplebim): 0.2284 m2; Thickness (Simplebim): 80 mm; Length (Simplebim): 1190 mm; Height (Simplebim): 2300 mm
ePset_Simplebim - Assembly Level: Leaf
ePset_LocationTool - Splitting: ORIGINAL
AVINOR - 05_ID-nummer: +TH=245.162; 08_Status: S4; 07_Fase: F90; 02_Prosjekt: A173040; 06_Omrade: TH; 03_Ansvar: 185239; 04_Kontrakt: 185259; 01_Lufthavnkode: ENGM
Pset_WallCommon - Reference: A270 - Åpning stål ramme for dører L-profil; IsExternal: no
Pset_QuantityTakeOff - Reference: A270 - Åpning stål ramme for dører L-profil; sets with these values: 2

# IfcWall: A270 KL-S04:A270 - L-profil (2)
In: Nivå F - 0,7 m
Pset_WallCommon - Reference: A270 - L-profil; IsExternal: no
ePset_Simplebim - Assembly Level: Leaf
AVINOR - 05_ID-nummer: +TH=245.162; 08_Status: S4; 07_Fase: F90; 02_Prosjekt: A173040; 06_Omrade: TH; 03_Ansvar: 185239; 04_Kontrakt: 185259; 01_Lufthavnkode: ENGM
ePset_SimplebimBasicQuantities - Length (Simplebim): 80 mm; Thickness (Simplebim): 40 mm
ePset_LocationTool - Splitting: ORIGINAL
Pset_QuantityTakeOff - Reference: A270 - L-profil; sets with these values: 2
Name (A270 KL-S04:A270 - L-profil:...) | Area, side, gross, larger (Simplebim) (m2) = Area, side, gross, smaller (Simplebim) (m2) = Area, side, gross, average (Simplebim) (m2) = Area, side, net, larger (Simplebim) (m2) = Area, side, net, smaller (Simplebim) (m2) = Area, side, net, average (Simplebim) (m2) | Area, side, gross, AABB (Simplebim) (m2) = Area, largest surface, net (Simplebim) (m2) | Height (Simplebim) (mm) | Volume, net (Simplebim) (m3)
49669625 | 0.1 | 0.2 | 2500 | 0.0014375
56755645 | 0.126 | 0.252 | 3150 | 0.00181125

# IfcWall: Basic Wall:A241 - RXVR-100, Basic Wall:A241 - RXVR-100:41929295
In: Nivå F - 0,7 m
Type - PredefinedType: STANDARD; Material: T2_Gips Robust 12.5 mm, _NSW X-finer 15 mm, _NSW Stålstender, uisolert 100 mm, T2_Gips Robust 12.5 mm
Type - Pset_WallCommon - AcousticRating: 48 dB
Type - Pset_ReinforcementBarPitchOfWall - Description: Stendervegg: 12.5mm Gipsplater - 100mm Stålstender - 15 mm x-finer + 12.5mm Gipsplater
ePset_Simplebim - Assembly Level: Leaf
Pset_QuantityTakeOff - Reference: A241 - RXVR-100; sets with these values: 2
ePset_SimplebimBasicQuantities - Volume, net (Simplebim): 1.62811 m3; Area, side, gross, larger (Simplebim): 14.3369 m2; Area, side, gross, average (Simplebim): 14.3369 m2; Area, side, gross, smaller (Simplebim): 14.3369 m2; Length (Simplebim): 4037.5 mm; Area, side, net, larger (Simplebim): 11.8283 m2; Area, side, net, average (Simplebim): 11.8283 m2; Area, side, net, smaller (Simplebim): 11.8283 m2; Area, largest surface, net (Simplebim): 11.8283 m2; Area, side, gross, AABB (Simplebim): 14.4139 m2; Thickness (Simplebim): 140 mm; Height (Simplebim): 3570 mm
AVINOR - 08_Status: S4; 07_Fase: F90; 05_ID-nummer: +TH=241.190; 02_Prosjekt: A173040; 06_Omrade: TH; 03_Ansvar: 185239; 04_Kontrakt: 185259; 01_Lufthavnkode: ENGM
ePset_LocationTool - Splitting: ORIGINAL
Pset_WallCommon - IsExternal: no; ExtendToStructure: no; LoadBearing: no; Reference: A241 - RXVR-100

# IfcWall: Basic Wall:A241 - RXVR-101, Basic Wall:A241 - RXVR-101:28979601
In: Nivå F - 0,7 m
Type - PredefinedType: STANDARD; Material: T2_Gips Robust 12.5 mm, T2_Gips Standard 12.5 mm, _NSW X-finer 15 mm, _NSW Stålstender, uisolert 100 mm, T2_Gips Standard 12.5 mm, T2_Gips Robust 12.5 mm
Type - Pset_WallCommon - AcousticRating: 48 dB
Type - Pset_ReinforcementBarPitchOfWall - Description: Stendervegg: 2x12.5mm Gipsplater - 100mm Stålstender - 15 mm x-finer + 2x12.5mm Gipsplater
ePset_LocationTool - Splitting: ORIGINAL
ePset_Simplebim - Assembly Level: Leaf
Pset_QuantityTakeOff - Reference: A241 - RXVR-101; sets with these values: 2
Identity Data - CQFireRequirement: EI 60/A2-s1,d0; CQAcousticRequirement: R'w 35dB
Pset_WallCommon - IsExternal: no; ExtendToStructure: no; LoadBearing: no; Reference: A241 - RXVR-101
AVINOR - 08_Status: S4; 07_Fase: F90; 05_ID-nummer: +TH=241.191; 02_Prosjekt: A173040; 06_Omrade: TH; 03_Ansvar: 185239; 04_Kontrakt: 185259; 01_Lufthavnkode: ENGM
ePset_SimplebimBasicQuantities - Length (Simplebim): 4162.5 mm; Area, side, gross, average (Simplebim): 14.7894 m2; Area, side, gross, smaller (Simplebim): 14.7894 m2; Area, side, gross, larger (Simplebim): 14.7894 m2; Area, largest surface, net (Simplebim): 12.5068 m2; Area, side, net, larger (Simplebim): 12.5068 m2; Area, side, net, average (Simplebim): 12.5068 m2; Area, side, net, smaller (Simplebim): 12.5068 m2; Area, side, gross, AABB (Simplebim): 14.8601 m2; Volume, net (Simplebim): 2.06363 m3; Thickness (Simplebim): 165 mm; Height (Simplebim): 3570 mm

# IfcWallStandardCase: Basic Wall:A240 - FE-S09 (4)
In: Nivå F - 0,7 m
Type - PredefinedType: STANDARD; Material: Rustfrit stål 5 mm
Type - Pset_ReinforcementBarPitchOfWall - Description: metallplate 5mm
Pset_WallCommon - Reference: A240 - FE-S09; IsExternal: no; ExtendToStructure: no; LoadBearing: no
ePset_Simplebim - Assembly Level: Leaf
ePset_LocationTool - Splitting: ORIGINAL
Pset_ReinforcementBarPitchOfWall - Reference: A240 - FE-S09; sets with these values: 2
AVINOR - 08_Status: S4; 07_Fase: F90; 02_Prosjekt: A173040; 06_Omrade: TH; 03_Ansvar: 185239; 04_Kontrakt: 185259; 05_ID-nummer: +TH=251.050-IY0009; 01_Lufthavnkode: ENGM
Name (Basic Wall:A240 - FE-S09:...)
35270608
35270609
35270613
35270614

# IfcWallStandardCase: Basic Wall:A241 - RXV-100, Basic Wall:A241 - RXV-100:44130124
In: Nivå F - 0,7 m
Type - PredefinedType: STANDARD; Material: T2_Gips Robust 12.5 mm, _NSW X-finer 15 mm, _NSW Stålstender, uisolert 100 mm
Type - Pset_ReinforcementBarPitchOfWall - Description: Tilsvarende: T2 - IVEGG-150 - Forprosjekt
ePset_SimplebimBasicQuantities - Area, side, gross, AABB (Simplebim): 44.4594 m2; Area, side, gross, smaller (Simplebim): 44.4594 m2; Area, side, gross, average (Simplebim): 44.4594 m2; Area, largest surface, net (Simplebim): 44.4594 m2; Area, side, gross, larger (Simplebim): 44.4594 m2; Area, side, net, smaller (Simplebim): 44.4594 m2; Area, side, net, average (Simplebim): 44.4594 m2; Area, side, net, larger (Simplebim): 44.4594 m2; Height (Simplebim): 3120 mm; Volume, net (Simplebim): 5.66857 m3; Length (Simplebim): 14249.8 mm; Thickness (Simplebim): 127.5 mm
ePset_Simplebim - Assembly Level: Leaf
ePset_LocationTool - Splitting: ORIGINAL
Pset_ReinforcementBarPitchOfWall - Reference: A241 - RXV-100; sets with these values: 2
AVINOR - 08_Status: S4; 07_Fase: F90; 05_ID-nummer: +TH=241.189; 02_Prosjekt: A173040; 06_Omrade: TH; 03_Ansvar: 185239; 04_Kontrakt: 185259; 01_Lufthavnkode: ENGM
Pset_WallCommon - IsExternal: no; ExtendToStructure: no; LoadBearing: no; Reference: A241 - RXV-100
